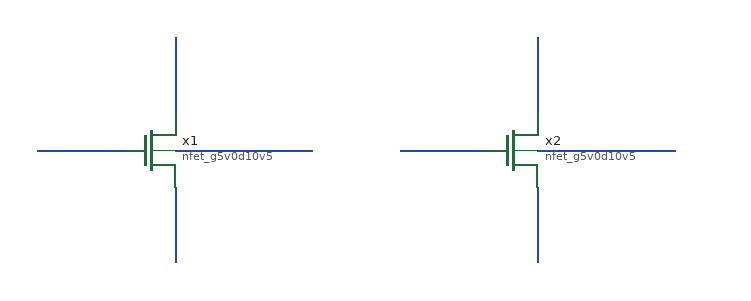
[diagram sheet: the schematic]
v {xschem version=3.1.0 file_version=1.2
}
G {}
K {}
V {}
S {}
E {}
N 500 -140 610 -140 {
lab=#net1}
N 500 -230 500 -170 {
lab=#net2}
N 390 -140 460 -140 {
lab=#net3}
N 500 -110 500 -50 {
lab=#net4}
N 790 -140 900 -140 {
lab=#net5}
N 790 -230 790 -170 {
lab=#net6}
N 680 -140 750 -140 {
lab=#net7}
N 790 -110 790 -50 {
lab=#net8}
C {nmosgen( @model )} 480 -140 0 0 {name=x1
model=nfet_g5v0d10v5}
C {nmosgen( @model )} 770 -140 0 0 {name=x2
model=nfet_g5v0d10v5}
